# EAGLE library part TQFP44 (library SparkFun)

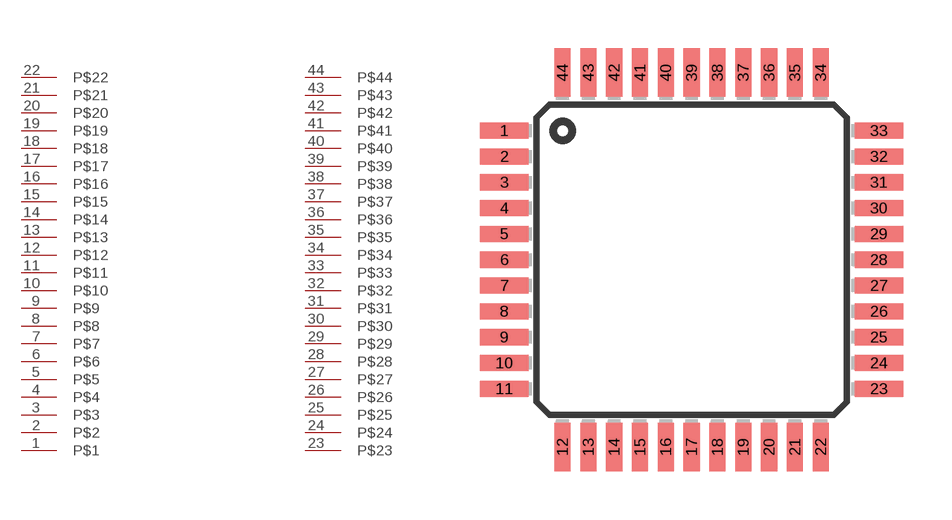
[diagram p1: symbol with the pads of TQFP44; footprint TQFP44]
Designator prefix -

## TQFP44  [TQFP44]
1  P$1
2  P$2
3  P$3
4  P$4
5  P$5
6  P$6
7  P$7
8  P$8
9  P$9
10  P$10
11  P$11
12  P$12
13  P$13
14  P$14
15  P$15
16  P$16
17  P$17
18  P$18
19  P$19
20  P$20
21  P$21
22  P$22
23  P$23
24  P$24
25  P$25
26  P$26
27  P$27
28  P$28
29  P$29
30  P$30
31  P$31
32  P$32
33  P$33
34  P$34
35  P$35
36  P$36
37  P$37
38  P$38
39  P$39
40  P$40
41  P$41
42  P$42
43  P$43
44  P$44

## Footprint TQFP44 (pad centres in mm)
smd 1.5 x 0.5: 1 1.82,10.35; 2 1.82,9.55; 3 1.82,8.75; 4 1.82,7.95; 5 1.82,7.15; 6 1.82,6.35; 7 1.82,5.55; 8 1.82,4.75; 9 1.82,3.95; 10 1.82,3.15; 11 1.82,2.35; 23 13.42,2.35; 24 13.42,3.15; 25 13.42,3.95; 26 13.42,4.75; 27 13.42,5.55; 28 13.42,6.35; 29 13.42,7.15; 30 13.42,7.95; 31 13.42,8.75; 32 13.42,9.55; 33 13.42,10.35
smd 0.5 x 1.5: 12 3.62,0.55; 13 4.42,0.55; 14 5.22,0.55; 15 6.02,0.55; 16 6.82,0.55; 17 7.62,0.55; 18 8.42,0.55; 19 9.22,0.55; 20 10.02,0.55; 21 10.82,0.55; 22 11.62,0.55; 34 11.62,12.15; 35 10.82,12.15; 36 10.02,12.15; 37 9.22,12.15; 38 8.42,12.15; 39 7.62,12.15; 40 6.82,12.15; 41 6.02,12.15; 42 5.22,12.15; 43 4.42,12.15; 44 3.62,12.15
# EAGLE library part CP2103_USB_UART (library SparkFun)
Single-Chip USB to UART Bridge Source: www.silabs.com .. CP2103.pdf. Spark Fun Electronics SKU : COM-00309

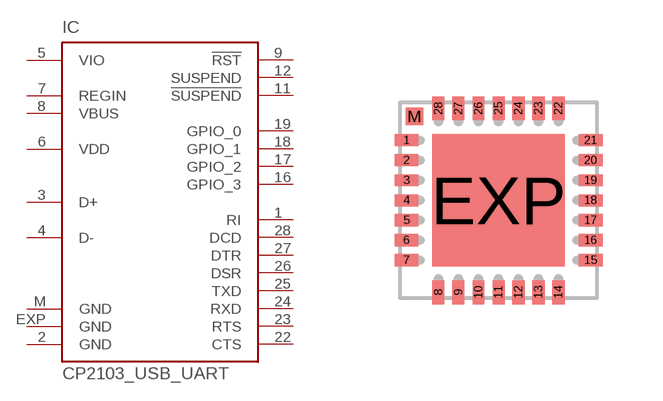
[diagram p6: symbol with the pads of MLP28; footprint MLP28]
Designator prefix IC

## CP2103_USB_UART  [MLP28]
1  RI  in
2  GND  pwr
3  D+
4  D-
5  VIO  pwr
6  VDD  pwr
7  REGIN  pas
8  VBUS  in
9  !RST
11  !SUSPEND  out
12  SUSPEND  out
16  GPIO_3
17  GPIO_2
18  GPIO_1
19  GPIO_0
22  CTS  in
23  RTS  out
24  RXD  in
25  TXD  out
26  DSR  in
27  DTR  out
28  DCD  in
EXP  GND  pwr
M  GND  pwr

## Footprint MLP28 (pad centres in mm)
MLP 28 Source: www.silabs.com .. CP2101.pdf
smd 0.6 x 0.3: 1 -2.3,1.5; 2 -2.3,1; 3 -2.3,0.5; 4 -2.3,0; 5 -2.3,-0.5; 6 -2.3,-1; 7 -2.3,-1.5; 15 2.3,-1.5; 16 2.3,-1; 17 2.3,-0.5; 18 2.3,0; 19 2.3,0.5; 20 2.3,1; 21 2.3,1.5
smd 0.3 x 0.6: 8 -1.5,-2.3; 9 -1,-2.3; 10 -0.5,-2.3; 11 0,-2.3; 12 0.5,-2.3; 13 1,-2.3; 14 1.5,-2.3; 22 1.5,2.3; 23 1,2.3; 24 0.5,2.3; 25 0,2.3; 26 -0.5,2.3; 27 -1,2.3; 28 -1.5,2.3
smd 3.3 x 3.3: EXP 0,0
smd 0.435 x 0.435: M -2.103,2.103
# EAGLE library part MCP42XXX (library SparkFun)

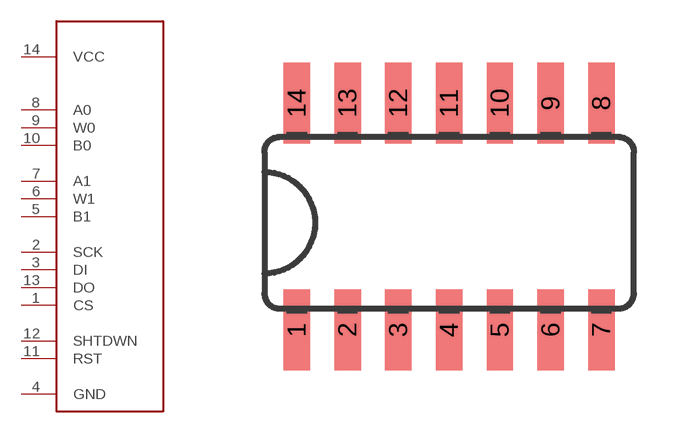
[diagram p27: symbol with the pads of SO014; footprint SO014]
Designator prefix U

## MCP42XXX  [SO014]
1  CS
2  SCK
3  DI
4  GND
5  B1
6  W1
7  A1
8  A0
9  W0
10  B0
11  RST
12  SHTDWN
13  DO
14  VCC

## Footprint SO014 (pad centres in mm)
smd 0.66 x 2.032: 1 -3.175,-2.68; 2 -1.905,-2.68; 3 -0.635,-2.68; 4 0.635,-2.68; 5 1.905,-2.68; 6 3.175,-2.68; 7 4.445,-2.68; 8 4.445,2.997; 9 3.175,2.997; 10 1.905,2.997; 11 0.635,2.997; 12 -0.635,2.997; 13 -1.905,2.997; 14 -3.175,2.997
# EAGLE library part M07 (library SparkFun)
Header 7 Standard 7-pin 0.1" header. Use with straight break away headers (SKU : PRT-00116), right angle break away headers (PRT-00553), swiss pins (PRT-00743), machine pins (PRT-00117), and female headers (PRT-00115).

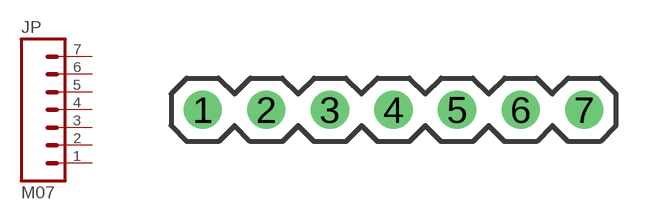
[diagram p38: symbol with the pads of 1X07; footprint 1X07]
Designator prefix JP

## M07  [1X07]
1  1  pas
2  2  pas
3  3  pas
4  4  pas
5  5  pas
6  6  pas
7  7  pas

## Footprint 1X07 (pad centres in mm)
drill 1.016 round: 1 0,0; 2 2.54,0; 3 5.08,0; 4 7.62,0; 5 10.16,0; 6 12.7,0; 7 15.24,0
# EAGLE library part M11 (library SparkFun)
Header 11 Standard 11-pin 0.1" header. Use with straight break away headers (SKU : PRT-00116), right angle break away headers (PRT-00553), swiss pins (PRT-00743), machine pins (PRT-00117), and female headers (PRT-00115).

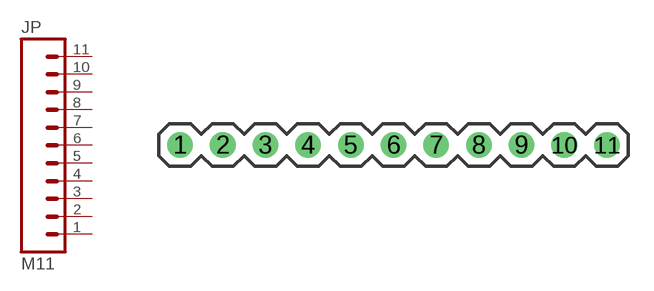
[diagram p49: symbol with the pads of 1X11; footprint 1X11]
Designator prefix JP

## M11PTH  [1X11]
1  1  pas
2  2  pas
3  3  pas
4  4  pas
5  5  pas
6  6  pas
7  7  pas
8  8  pas
9  9  pas
10  10  pas
11  11  pas

## Footprint 1X11 (pad centres in mm)
drill 1.016 round: 1 0,0; 2 2.54,0; 3 5.08,0; 4 7.62,0; 5 10.16,0; 6 12.7,0; 7 15.24,0; 8 17.78,0; 9 20.32,0; 10 22.86,0; 11 25.4,0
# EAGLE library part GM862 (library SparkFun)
GM862 Cellular Module with GPS Proven layout and schematic for GM862 cellular module with SiRF III GPS. Spark Fun Electronics SKU : CEL-07917

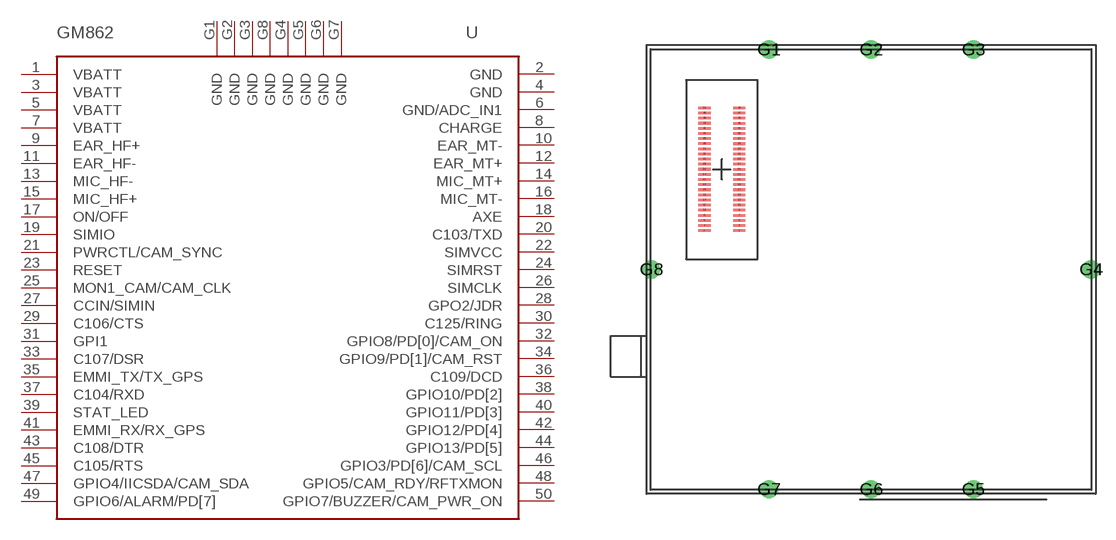
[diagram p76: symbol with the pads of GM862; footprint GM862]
Designator prefix -

## GM862GND  [GM862]
1  VBATT
2  GND
3  VBATT
4  GND
5  VBATT
6  GND/ADC_IN1
7  VBATT
8  CHARGE
9  EAR_HF+
10  EAR_MT-
11  EAR_HF-
12  EAR_MT+
13  MIC_HF-
14  MIC_MT+
15  MIC_HF+
16  MIC_MT-
17  ON/OFF
18  AXE
19  SIMIO
20  C103/TXD
21  PWRCTL/CAM_SYNC
22  SIMVCC
23  RESET
24  SIMRST
25  MON1_CAM/CAM_CLK
26  SIMCLK
27  CCIN/SIMIN
28  GPO2/JDR
29  C106/CTS
30  C125/RING
31  GPI1
32  GPIO8/PD[0]/CAM_ON
33  C107/DSR
34  GPIO9/PD[1]/CAM_RST
35  EMMI_TX/TX_GPS
36  C109/DCD
37  C104/RXD
38  GPIO10/PD[2]
39  STAT_LED
40  GPIO11/PD[3]
41  EMMI_RX/RX_GPS
42  GPIO12/PD[4]
43  C108/DTR
44  GPIO13/PD[5]
45  C105/RTS
46  GPIO3/PD[6]/CAM_SCL
47  GPIO4/IICSDA/CAM_SDA
48  GPIO5/CAM_RDY/RFTXMON
49  GPIO6/ALARM/PD[7]
50  GPIO7/BUZZER/CAM_PWR_ON
G1  GND
G2  GND
G3  GND
G4  GND
G5  GND
G6  GND
G7  GND
G8  GND

## Footprint GM862 (pad centres in mm)
smd 1.2 x 0.25: 1 -12.898,3.788; 2 -16.298,3.792; 3 -12.898,4.288; 4 -16.298,4.292; 5 -12.898,4.788; 6 -16.298,4.792; 7 -12.898,5.288; 8 -16.298,5.292; 9 -12.898,5.788; 10 -16.298,5.792; 11 -12.899,6.287; 12 -16.298,6.292; 13 -12.898,6.788; 14 -16.298,6.792; 15 -12.898,7.288; 16 -16.298,7.292; 17 -12.898,7.788; 18 -16.298,7.792; 19 -12.898,8.288; 20 -16.298,8.292; 21 -12.898,8.788; 22 -16.298,8.792; 23 -12.898,9.288; 24 -16.298,9.292; 25 -12.898,9.788; 26 -16.298,9.792; 27 -12.898,10.288; 28 -16.298,10.292; 29 -12.898,10.788; 30 -16.298,10.792; 31 -12.898,11.288; 32 -16.298,11.292; 33 -12.898,11.788; 34 -16.298,11.792; 35 -12.898,12.288; 36 -16.298,12.292; 37 -12.898,12.788; 38 -16.298,12.792; 39 -12.898,13.288; 40 -16.298,13.292; 41 -12.898,13.788; 42 -16.298,13.792; 43 -12.898,14.288; 44 -16.298,14.292; 45 -12.898,14.788; 46 -16.298,14.792; 47 -12.898,15.288; 48 -16.298,15.292; 49 -12.898,15.788; 50 -16.298,15.792
drill 1.2 round: G1 -10,21.5; G2 0,21.5; G3 10,21.5; G4 21.5,0; G5 10,-21.5; G6 0,-21.5; G7 -10,-21.5; G8 -21.5,0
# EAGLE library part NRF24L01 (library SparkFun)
2.4GHz Low Power Transceiver This is the very popular, low cost, very low power RF transceiver from Nordic Semiconductor. Simple SPI interface. SKU: COM-00690

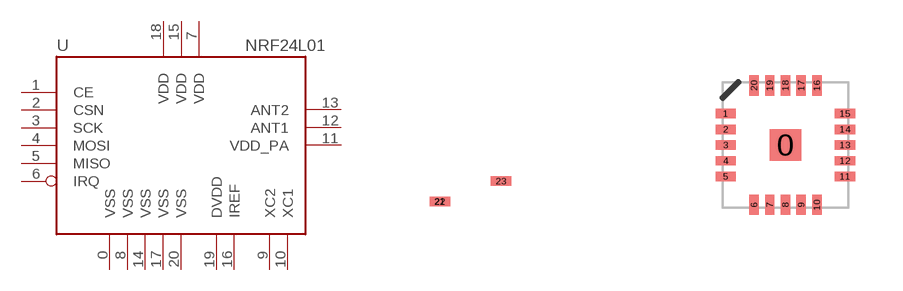
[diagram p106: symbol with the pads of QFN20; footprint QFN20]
Designator prefix -

## NRF24L01SMD  [QFN20]
0  VSS  pwr
1  CE  in
2  CSN  in
3  SCK  in
4  MOSI  in
5  MISO  out
6  IRQ  out
7  VDD  pwr
8  VSS  pwr
9  XC2  in
10  XC1  in
11  VDD_PA  pwr
12  ANT1  out
13  ANT2  out
14  VSS  pwr
15  VDD  pwr
16  IREF  in
17  VSS  pwr
18  VDD  pwr
19  DVDD  pwr
20  VSS  pwr

## Footprint QFN20 (pad centres in mm)
smd 1 x 1: 0 0,0
smd 0.65 x 0.3: 1 -1.9,1; 2 -1.9,0.5; 3 -1.9,0; 4 -1.9,-0.5; 5 -1.9,-1; 11 1.9,-1; 12 1.9,-0.5; 13 1.9,0; 14 1.9,0.5; 15 1.9,1; 21 -11,-1.8; 22 -11,-1.8; 23 -9.05,-1.15
smd 0.3 x 0.65: 6 -1,-1.9; 7 -0.5,-1.9; 8 0,-1.9; 9 0.5,-1.9; 10 1,-1.9; 16 1,1.9; 17 0.5,1.9; 18 0,1.9; 19 -0.5,1.9; 20 -1,1.9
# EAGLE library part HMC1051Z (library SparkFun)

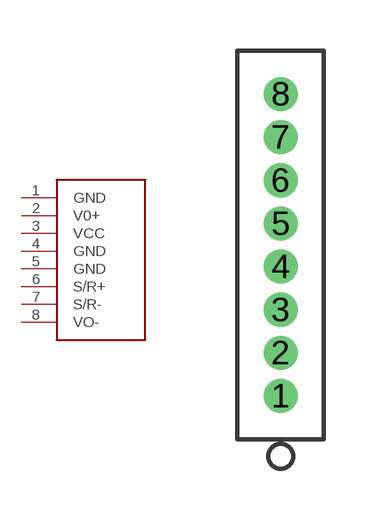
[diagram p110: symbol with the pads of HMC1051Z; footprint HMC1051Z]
Designator prefix -

## HMC1051Z  [HMC1051Z]
1  GND
2  V0+
3  VCC
4  GND
5  GND
6  S/R+
7  S/R-
8  VO-

## Footprint HMC1051Z (pad centres in mm)
drill 0.5 round: 1 0,0; 2 0,1.27; 3 0,2.54; 4 0,3.81; 5 0,5.08; 6 0,6.35; 7 0,7.62; 8 0,8.89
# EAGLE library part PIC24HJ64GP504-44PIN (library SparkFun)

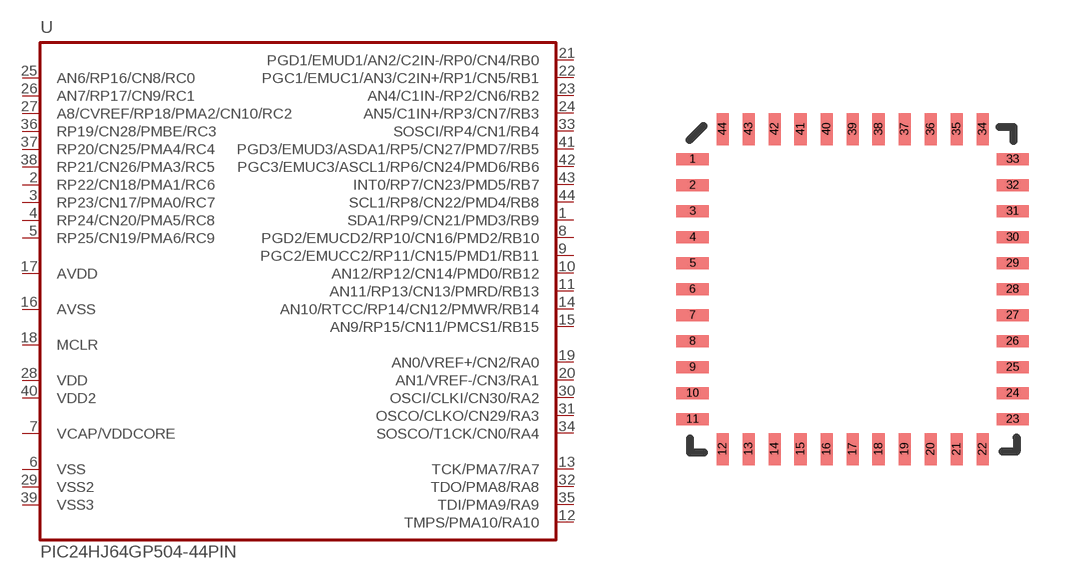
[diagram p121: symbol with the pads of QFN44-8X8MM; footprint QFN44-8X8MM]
Designator prefix -

## PIC24HJ64GP504-44PIN  [QFN44-8X8MM]
1  SDA1/RP9/CN21/PMD3/RB9
2  RP22/CN18/PMA1/RC6
3  RP23/CN17/PMA0/RC7
4  RP24/CN20/PMA5/RC8
5  RP25/CN19/PMA6/RC9
6  VSS  pwr
7  VCAP/VDDCORE
8  PGD2/EMUCD2/RP10/CN16/PMD2/RB10
9  PGC2/EMUCC2/RP11/CN15/PMD1/RB11
10  AN12/RP12/CN14/PMD0/RB12
11  AN11/RP13/CN13/PMRD/RB13
12  TMPS/PMA10/RA10
13  TCK/PMA7/RA7
14  AN10/RTCC/RP14/CN12/PMWR/RB14
15  AN9/RP15/CN11/PMCS1/RB15
16  AVSS  pwr
17  AVDD  pwr
18  MCLR
19  AN0/VREF+/CN2/RA0
20  AN1/VREF-/CN3/RA1
21  PGD1/EMUD1/AN2/C2IN-/RP0/CN4/RB0
22  PGC1/EMUC1/AN3/C2IN+/RP1/CN5/RB1
23  AN4/C1IN-/RP2/CN6/RB2
24  AN5/C1IN+/RP3/CN7/RB3
25  AN6/RP16/CN8/RC0
26  AN7/RP17/CN9/RC1
27  A8/CVREF/RP18/PMA2/CN10/RC2
28  VDD  pwr
29  VSS2  pwr
30  OSCI/CLKI/CN30/RA2
31  OSCO/CLKO/CN29/RA3
32  TDO/PMA8/RA8
33  SOSCI/RP4/CN1/RB4
34  SOSCO/T1CK/CN0/RA4
35  TDI/PMA9/RA9
36  RP19/CN28/PMBE/RC3
37  RP20/CN25/PMA4/RC4
38  RP21/CN26/PMA3/RC5
39  VSS3  pwr
40  VDD2  pwr
41  PGD3/EMUD3/ASDA1/RP5/CN27/PMD7/RB5
42  PGC3/EMUC3/ASCL1/RP6/CN24/PMD6/RB6
43  INT0/RP7/CN23/PMD5/RB7
44  SCL1/RP8/CN22/PMD4/RB8

## Footprint QFN44-8X8MM (pad centres in mm)
smd 0.8 x 0.3: 1 -0.4,6.65; 2 -0.4,6; 3 -0.4,5.35; 4 -0.4,4.7; 5 -0.4,4.05; 6 -0.4,3.4; 7 -0.4,2.75; 8 -0.4,2.1; 9 -0.4,1.45; 10 -0.4,0.8; 11 -0.4,0.15; 23 7.6,0.15; 24 7.6,0.8; 25 7.6,1.45; 26 7.6,2.1; 27 7.6,2.75; 28 7.6,3.4; 29 7.6,4.05; 30 7.6,4.7; 31 7.6,5.35; 32 7.6,6; 33 7.6,6.65
smd 0.3 x 0.8: 12 0.35,-0.6; 13 1,-0.6; 14 1.65,-0.6; 15 2.3,-0.6; 16 2.95,-0.6; 17 3.6,-0.6; 18 4.25,-0.6; 19 4.9,-0.6; 20 5.55,-0.6; 21 6.2,-0.6; 22 6.85,-0.6; 34 6.85,7.4; 35 6.2,7.4; 36 5.55,7.4; 37 4.9,7.4; 38 4.25,7.4; 39 3.6,7.4; 40 2.95,7.4; 41 2.3,7.4; 42 1.65,7.4; 43 1,7.4; 44 0.35,7.4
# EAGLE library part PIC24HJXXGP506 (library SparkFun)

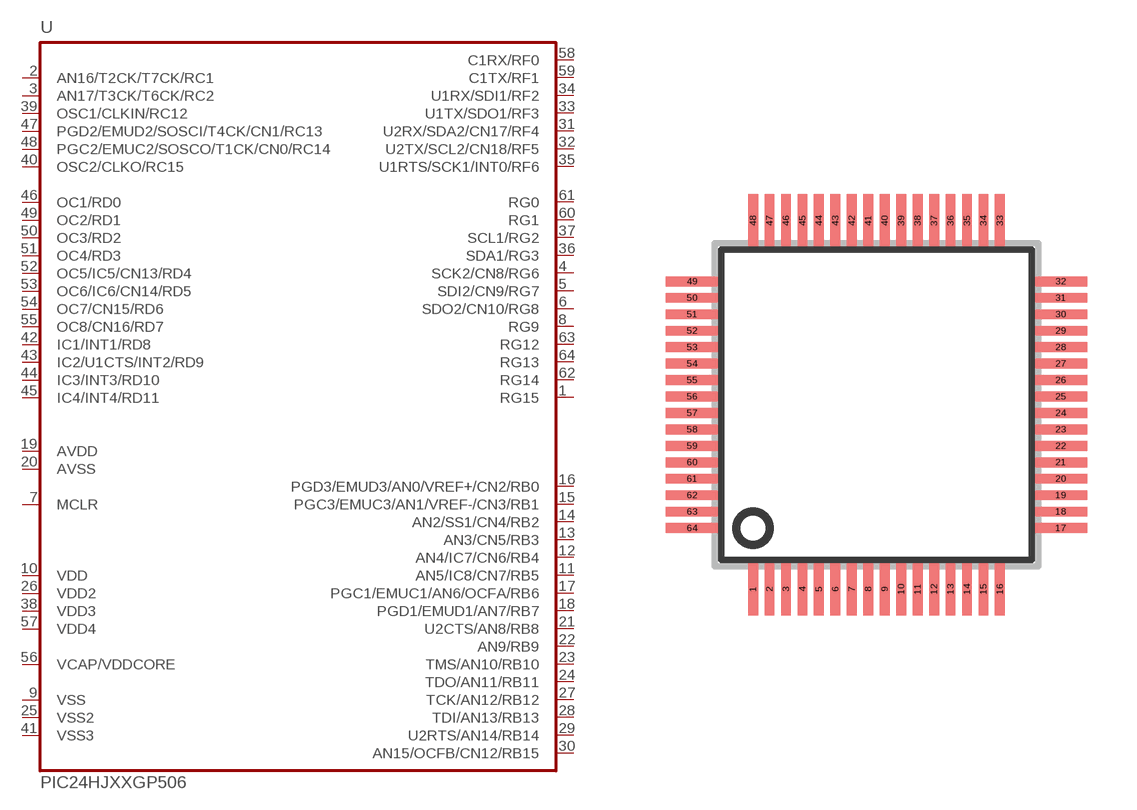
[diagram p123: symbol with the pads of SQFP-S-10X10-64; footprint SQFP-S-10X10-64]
Designator prefix -

## PIC24HJXXGP506  [SQFP-S-10X10-64]
1  RG15
2  AN16/T2CK/T7CK/RC1
3  AN17/T3CK/T6CK/RC2
4  SCK2/CN8/RG6
5  SDI2/CN9/RG7
6  SDO2/CN10/RG8
7  MCLR
8  RG9
9  VSS  pwr
10  VDD  pwr
11  AN5/IC8/CN7/RB5
12  AN4/IC7/CN6/RB4
13  AN3/CN5/RB3
14  AN2/SS1/CN4/RB2
15  PGC3/EMUC3/AN1/VREF-/CN3/RB1
16  PGD3/EMUD3/AN0/VREF+/CN2/RB0
17  PGC1/EMUC1/AN6/OCFA/RB6
18  PGD1/EMUD1/AN7/RB7
19  AVDD  pwr
20  AVSS  pwr
21  U2CTS/AN8/RB8
22  AN9/RB9
23  TMS/AN10/RB10
24  TDO/AN11/RB11
25  VSS2  pwr
26  VDD2  pwr
27  TCK/AN12/RB12
28  TDI/AN13/RB13
29  U2RTS/AN14/RB14
30  AN15/OCFB/CN12/RB15
31  U2RX/SDA2/CN17/RF4
32  U2TX/SCL2/CN18/RF5
33  U1TX/SDO1/RF3
34  U1RX/SDI1/RF2
35  U1RTS/SCK1/INT0/RF6
36  SDA1/RG3
37  SCL1/RG2
38  VDD3  pwr
39  OSC1/CLKIN/RC12
40  OSC2/CLKO/RC15
41  VSS3  pwr
42  IC1/INT1/RD8
43  IC2/U1CTS/INT2/RD9
44  IC3/INT3/RD10
45  IC4/INT4/RD11
46  OC1/RD0
47  PGD2/EMUD2/SOSCI/T4CK/CN1/RC13
48  PGC2/EMUC2/SOSCO/T1CK/CN0/RC14
49  OC2/RD1
50  OC3/RD2
51  OC4/RD3
52  OC5/IC5/CN13/RD4
53  OC6/IC6/CN14/RD5
54  OC7/CN15/RD6
55  OC8/CN16/RD7
56  VCAP/VDDCORE
57  VDD4  pwr
58  C1RX/RF0
59  C1TX/RF1
60  RG1
61  RG0
62  RG14
63  RG12
64  RG13

## Footprint SQFP-S-10X10-64 (pad centres in mm)
QFP64 shrink quad flat pack, square
smd 0.3 x 1.6: 1 -3.75,-5.6; 2 -3.25,-5.6; 3 -2.75,-5.6; 4 -2.25,-5.6; 5 -1.75,-5.6; 6 -1.25,-5.6; 7 -0.75,-5.6; 8 -0.25,-5.6; 9 0.25,-5.6; 10 0.75,-5.6; 11 1.25,-5.6; 12 1.75,-5.6; 13 2.25,-5.6; 14 2.75,-5.6; 15 3.25,-5.6; 16 3.75,-5.6; 33 3.75,5.6; 34 3.25,5.6; 35 2.75,5.6; 36 2.25,5.6; 37 1.75,5.6; 38 1.25,5.6; 39 0.75,5.6; 40 0.25,5.6; 41 -0.25,5.6; 42 -0.75,5.6; 43 -1.25,5.6; 44 -1.75,5.6; 45 -2.25,5.6; 46 -2.75,5.6; 47 -3.25,5.6; 48 -3.75,5.6
smd 1.6 x 0.3: 17 5.6,-3.75; 18 5.6,-3.25; 19 5.6,-2.75; 20 5.6,-2.25; 21 5.6,-1.75; 22 5.6,-1.25; 23 5.6,-0.75; 24 5.6,-0.25; 25 5.6,0.25; 26 5.6,0.75; 27 5.6,1.25; 28 5.6,1.75; 29 5.6,2.25; 30 5.6,2.75; 31 5.6,3.25; 32 5.6,3.75; 49 -5.6,3.75; 50 -5.6,3.25; 51 -5.6,2.75; 52 -5.6,2.25; 53 -5.6,1.75; 54 -5.6,1.25; 55 -5.6,0.75; 56 -5.6,0.25; 57 -5.6,-0.25; 58 -5.6,-0.75; 59 -5.6,-1.25; 60 -5.6,-1.75; 61 -5.6,-2.25; 62 -5.6,-2.75; 63 -5.6,-3.25; 64 -5.6,-3.75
